PROGRAM p04_samoPrviCikel
VAR
	M0: BOOL;
	M1: BOOL;
END_VAR

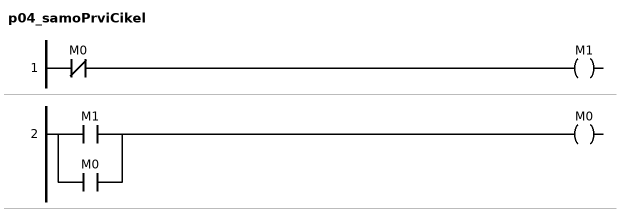
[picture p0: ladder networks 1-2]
// NETWORK 1
M1 := NOT M0;

// NETWORK 2
M0 := M1 OR M0;

END_PROGRAM
